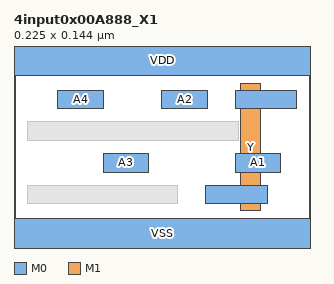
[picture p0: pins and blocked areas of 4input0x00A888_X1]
MACRO 4input0x00A888_X1
  CLASS CORE ;
  ORIGIN 0 0 ;
  FOREIGN 4input0x00A888_X1 0 0 ;
  SIZE 0.2250 BY 0.1440 ;
  SYMMETRY X Y ;
  SITE coresite ;
  PIN A1
    DIRECTION INPUT ;
    USE SIGNAL ;
    PORT
      LAYER M0 ;
        RECT 0.1680 0.0530 0.2020 0.0670 ;
    END
  END A1
  PIN A2
    DIRECTION INPUT ;
    USE SIGNAL ;
    PORT
      LAYER M0 ;
        RECT 0.1120 0.1010 0.1470 0.1150 ;
    END
  END A2
  PIN A3
    DIRECTION INPUT ;
    USE SIGNAL ;
    PORT
      LAYER M0 ;
        RECT 0.0680 0.0530 0.1020 0.0670 ;
    END
  END A3
  PIN A4
    DIRECTION INPUT ;
    USE SIGNAL ;
    PORT
      LAYER M0 ;
        RECT 0.0330 0.1010 0.0680 0.1150 ;
    END
  END A4
  PIN Y
    DIRECTION OUTPUT ;
    USE SIGNAL ;
    PORT
      LAYER M1 ;
        RECT 0.1720 0.0240 0.1870 0.1200 ;
      LAYER M0 ;
        RECT 0.1680 0.1010 0.2140 0.1150 ;
        RECT 0.1450 0.0290 0.1920 0.0430 ;
    END
  END Y
  PIN VDD
    DIRECTION INOUT ;
    USE POWER ;
    SHAPE ABUTMENT ;
    PORT
      LAYER M0 ;
        RECT 0.0000 0.1260 0.2250 0.1620 ;
    END
  END VDD
  PIN VSS
    DIRECTION INOUT ;
    USE GROUND ;
    SHAPE ABUTMENT ;
    PORT
      LAYER M0 ;
        RECT 0.0000 -0.0180 0.2250 0.0180 ;
    END
  END VSS
  OBS
    LAYER V0 ;
      RECT 0.1730 0.1010 0.1870 0.1150 ;
      RECT 0.1730 0.0290 0.1870 0.0430 ;
    LAYER M0 ;
      RECT 0.0100 0.0290 0.1240 0.0430 ;
      RECT 0.0100 0.0770 0.1700 0.0910 ;
  END
END 4input0x00A888_X1
